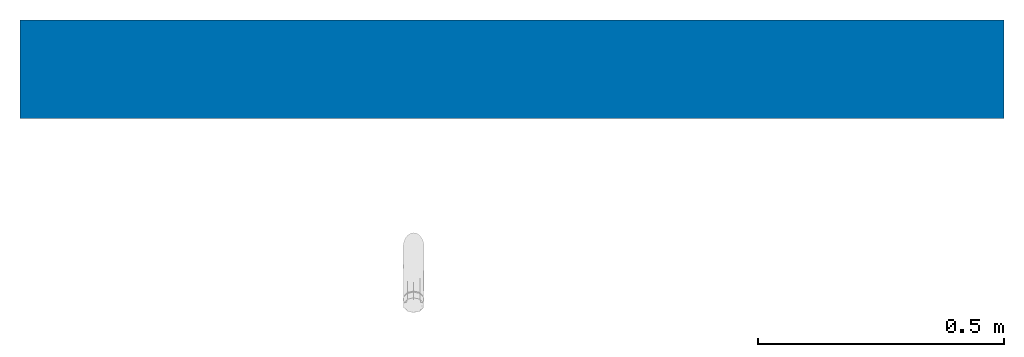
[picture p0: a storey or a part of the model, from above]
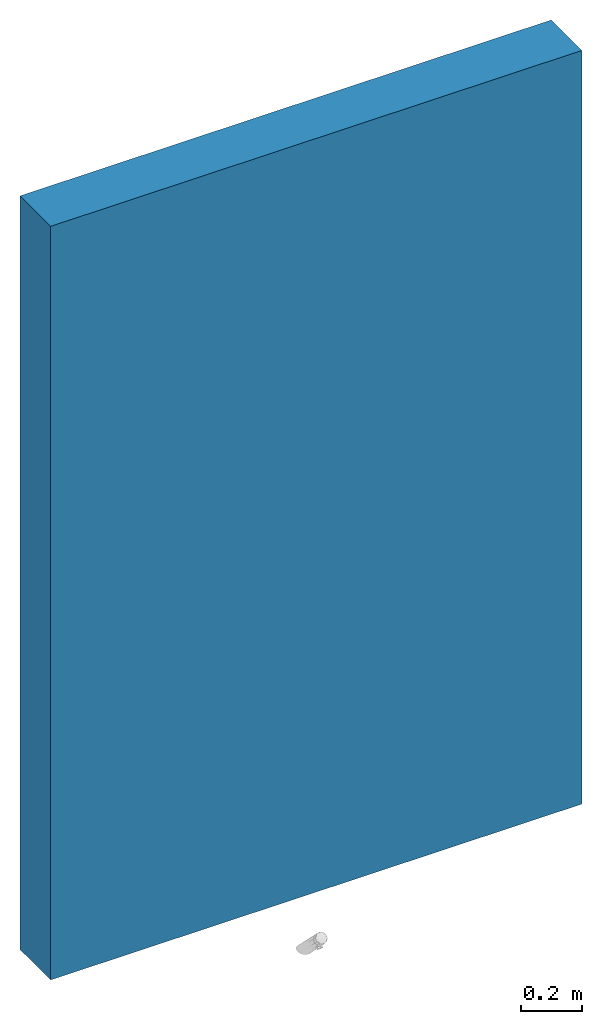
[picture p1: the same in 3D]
Properties of the parts of a building model (IFC2X3)

# File
Description: ViewDefinition [CoordinationView]
File name: Project Number
Time: 2016-07-12T09:40:47
Written by: Autodesk Revit Architecture 2011 - 1.0
Made in: 20100326_1700(x64)

# IfcProject, Project Number
Phase: Project Status

# IfcSite, Default
RefLatitude: 42, 21, 30, 344238; RefLongitude: -71, -3, -35, -194702; RefElevation: 0 mm

# IfcBuilding
Pset_BuildingCommon - NumberOfStoreys: 1
PSet_Revit_Other - Project Issue Date: Issue Date; Project Status: Project Status; Client Name: Owner; Project Address: Enter address here; Project Name: Project Name; Project Number: Project Number

# IfcBuildingStorey, Level 1
Elevation: 0 mm
PSet_Revit_Identity Data - Name: Level 1
PSet_Revit_Constraints - Elevation: 0 mm
PSet_Revit_Type_Graphics - Line Weight: 1; Color: 0; Line Pattern: Centre; Symbol: M_Level Head - Circle; Symbol at End 1 Default: no; Symbol at End 2 Default: yes
PSet_Revit_Type_Constraints - Elevation Base: 0
PSet_Revit_Type_Dimensions - Automatic Room Computation Height: no; Computation Height: 1200 mm

# IfcBuildingElementProxy: 794100, 794100:794100:794100:180717
In: Level 1
PSet_Revit_Constraints - Level: Level 1; Host: Level : Level 1; Offset: 0 mm
PSet_Revit_Mechanical - System Type: Domestic Hot Water,Domestic Cold Water; System Name: Default Domestic Hot Water (Polantis_Production),Default Domestic Cold Water (Polantis_Production)
PSet_Revit_Identity Data - Mark: 24
PSet_Revit_Phasing - Phase Created: New Construction
PSet_Revit_Type_Data - WaterSupplyTemperatureMaximum: 55°C-85° (?50°C : CW/HW); Operation: Single control time flow mixer; IntegralAccessoryOptions: Thermostatic mixing valve; IntegralAccessory: PEX flexibles; FlowRate lps: 0,05 lps at 3 bar; FlowRate lpm: 3 lpm at 3 bar
PSet_Revit_Type_Other - WarrantyDurationUnit: 10 years; WarrantyDescription: Any manufacturing defect; SerialNumber: 3456330136433; NominalLength: 105 mm; NominalHeight: 70 mm; Name: TEMPOMIX 3; ModelNumber: 794100; Material: Solid brass; Grade: ACS - BELGAQUA - PZH; Finish: Chrome-plated; Features: Deck-mounted single control time flow basin mixer: Soft-touch operation. Temperature control and operation on the push-button. Time flow pre-set at ~7 sec. (can be adjusted from 3 to 10 sec.). Flow rate pre-set at 3 lpm at 3 bar, can be adjusted from 1.5 to 6 lpm. Tamperproof scale-resistant flow straightener. Chrome-plated solid brass body. PEX flexibles F3/8" with filters and non-return valves. Reinforced fixing. Adjustable maximum temperature limiter.
PSet_Revit_Type_General - Version: v1; ProductInformation: http://www.delabie.com/products/794100; ManufacturerURL: http://www.delabie.com; ManufacturerName: DELABIE; Category: Basin mixer
PSet_Revit_Type_Identity Data - Description: French manufacturer Delabie is a leader in the European sanitary ware market for non-domestic places. Water controls, solutions for disabled people, sanitary ware, for schools, leisure centres, offices, hospitals, airports…; URL: http://www.delabie.com; Type Comments: Deck-mounted time flow mixer; Model: TEMPOMIX 3; Manufacturer: DELABIE
PSet_Revit_Type_Dimensions - Radius: 7.6 mm

# IfcWallStandardCase: Basic Wall:Generic - 200mm:398, Basic Wall:Generic - 200mm:127613
In: Level 1
Material: Default Wall 200 mm
Pset_WallCommon - Reference: Basic Wall:Generic - 200mm; LoadBearing: no; ExtendToStructure: no; IsExternal: yes
PSet_Revit_Constraints - Location Line: 0; Base Constraint: Level 1; Base Offset: 0 mm; Base is Attached: no; Base Extension Distance: 0 mm; Unconnected Height: 3000 mm; Top Offset: 0 mm; Top is Attached: no; Top Extension Distance: 0 mm; Room Bounding: yes; Related to Mass: no
PSet_Revit_Phasing - Phase Created: New Construction
PSet_Revit_Structural - Structural Usage: 0
PSet_Revit_Dimensions - Length: 2000 mm; Area: 6000000 mm2; Volume: 1200000000 mm3
PSet_Revit_Type_Construction - Wrapping at Inserts: 0; Wrapping at Ends: 0; Width: 200 mm; Function: 1
PSet_Revit_Type_Graphics - Coarse Scale Fill Color: 0
